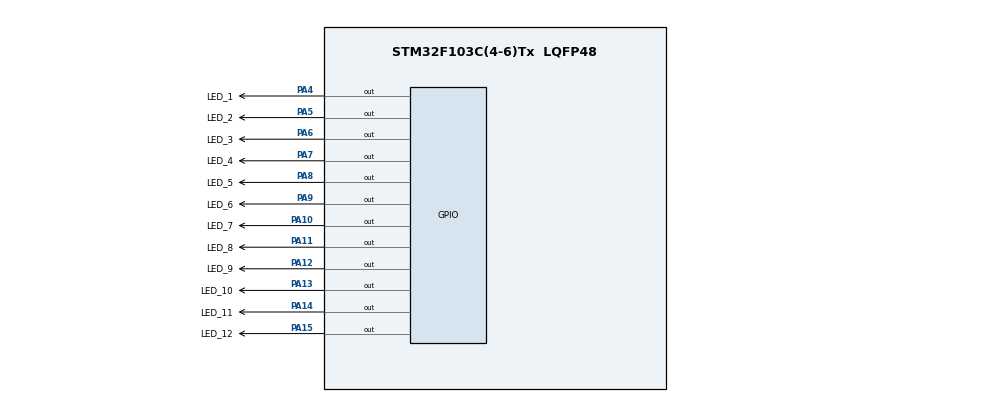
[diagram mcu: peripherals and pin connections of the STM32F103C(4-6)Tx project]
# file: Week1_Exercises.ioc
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Mcu.Family=STM32F1
Mcu.Name=STM32F103C(4-6)Tx
Mcu.Package=LQFP48
NVIC.PriorityGroup=NVIC_PRIORITYGROUP_4
PA10.GPIO_Label=LED_7
PA10.Signal=GPIO_Output
PA11.GPIO_Label=LED_8
PA11.Signal=GPIO_Output
PA12.GPIO_Label=LED_9
PA12.Signal=GPIO_Output
PA13.GPIO_Label=LED_10
PA13.Signal=GPIO_Output
PA14.GPIO_Label=LED_11
PA14.Signal=GPIO_Output
PA15.GPIO_Label=LED_12
PA15.Signal=GPIO_Output
PA4.GPIO_Label=LED_1
PA4.Signal=GPIO_Output
PA5.GPIO_Label=LED_2
PA5.Signal=GPIO_Output
PA6.GPIO_Label=LED_3
PA6.Signal=GPIO_Output
PA7.GPIO_Label=LED_4
PA7.Signal=GPIO_Output
PA8.GPIO_Label=LED_5
PA8.Signal=GPIO_Output
PA9.GPIO_Label=LED_6
PA9.Signal=GPIO_Output
ProjectManager.HeapSize=0x200
ProjectManager.StackSize=0x400
ProjectManager.TargetToolchain=STM32CubeIDE
RCC.APB1Freq_Value=8000000
RCC.APB2Freq_Value=8000000
VP_SYS_VS_ND.Mode=No_Debug
board=custom

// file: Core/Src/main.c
/* USER CODE BEGIN Header */
/**
  ******************************************************************************
  * @file           : main.c
  * @brief          : Main program body
  ******************************************************************************
  * @attention
  *
  * <h2><center>&copy; Copyright (c) 2021 STMicroelectronics.
  * All rights reserved.</center></h2>
  *
  * This software component is licensed by ST under BSD 3-Clause license,
  * the "License"; You may not use this file except in compliance with the
  * License. You may obtain a copy of the License at:
  *                        opensource.org/licenses/BSD-3-Clause
  *
  ******************************************************************************
  */
/* USER CODE END Header */
#include "main.h"
#include "led_display.h"

void SystemClock_Config(void);
static void MX_GPIO_Init(void);

int main(void)
{

  /* MCU Configuration--------------------------------------------------------*/

  /* Reset of all peripherals, Initializes the Flash interface and the Systick. */
  HAL_Init();

  /* Configure the system clock */
  SystemClock_Config();

  /* Initialize all configured peripherals */
  MX_GPIO_Init();

  /* Infinite loop */
  /* USER CODE BEGIN WHILE */
  int counter = 0;
  while (1)
  {
    /* USER CODE END WHILE */

    /* USER CODE BEGIN 3 */
	HAL_GPIO_WritePin (LED_1_RED_GPIO_Port, LED_1_RED_Pin, 0);
	HAL_GPIO_WritePin (LED_2_YELLOW_GPIO_Port, LED_2_YELLOW_Pin, 0);
	HAL_GPIO_WritePin (LED_3_GREEN_GPIO_Port, LED_3_GREEN_Pin, 0);
	HAL_GPIO_WritePin (LED_4_RED_GPIO_Port, LED_4_RED_Pin, 0);
	HAL_GPIO_WritePin (LED_5_YELLOW_GPIO_Port, LED_5_YELLOW_Pin, 0);
	HAL_GPIO_WritePin (LED_6_GREEN_GPIO_Port, LED_6_GREEN_Pin, 0);

	// Exercise 4: Count up
//	HAL_GPIO_WritePin (LED_1_RED_GPIO_Port, LED_1_RED_Pin, 1);
//
//	counter = 0;
//	while(counter >= 1){
//		HAL_GPIO_WritePin (LED_5_YELLOW_GPIO_Port, LED_5_YELLOW_Pin, 1);
//		update_seven_segment_led_buffer(counter--);
//		seven_segment_led_driver();
//		HAL_Delay(1000);
//	}
//	HAL_GPIO_WritePin (LED_5_YELLOW_GPIO_Port, LED_5_YELLOW_Pin, 0);
//	counter = 0;
//	while(counter >= 3){
//		HAL_GPIO_WritePin (LED_6_GREEN_GPIO_Port, LED_6_GREEN_Pin, 1);
//		update_seven_segment_led_buffer(counter--);
//		seven_segment_led_driver();
//		HAL_Delay(1000);
//	}
//	HAL_GPIO_WritePin (LED_6_GREEN_GPIO_Port, LED_6_GREEN_Pin, 0);
//
//	HAL_GPIO_WritePin (LED_4_RED_GPIO_Port, LED_4_RED_Pin, 1);
//
//	counter = 0;
//		while(counter >= 1){
//		HAL_GPIO_WritePin (LED_2_YELLOW_GPIO_Port, LED_2_YELLOW_Pin, 1);
//		update_seven_segment_led_buffer(counter--);
//		seven_segment_led_driver();
//		HAL_Delay(1000);
//		}
//	HAL_GPIO_WritePin (LED_2_YELLOW_GPIO_Port, LED_2_YELLOW_Pin, 0);
//	counter = 0;
//	while(counter >= 3){
//		HAL_GPIO_WritePin (LED_1_RED_GPIO_Port, LED_1_RED_Pin, 0);
//		HAL_GPIO_WritePin (LED_3_GREEN_GPIO_Port, LED_3_GREEN_Pin, 1);
//		update_seven_segment_led_buffer(counter--);
//		seven_segment_led_driver();
//		HAL_Delay(1000);
//	}
//	HAL_GPIO_WritePin (LED_3_GREEN_GPIO_Port, LED_3_GREEN_Pin, 0);

	// Exercise 5: Count down
	HAL_GPIO_WritePin (LED_1_RED_GPIO_Port, LED_1_RED_Pin, 1);

	counter = 1;
	while(counter >= 0){
		HAL_GPIO_WritePin (LED_5_YELLOW_GPIO_Port, LED_5_YELLOW_Pin, 1);
		update_seven_segment_led_buffer(counter--);
		seven_segment_led_driver();
		HAL_Delay(1000);
	}
	HAL_GPIO_WritePin (LED_5_YELLOW_GPIO_Port, LED_5_YELLOW_Pin, 0);
	counter = 3;
	while(counter >= 0){
		HAL_GPIO_WritePin (LED_6_GREEN_GPIO_Port, LED_6_GREEN_Pin, 1);
		update_seven_segment_led_buffer(counter--);
		seven_segment_led_driver();
		HAL_Delay(1000);
	}
	HAL_GPIO_WritePin (LED_6_GREEN_GPIO_Port, LED_6_GREEN_Pin, 0);

	HAL_GPIO_WritePin (LED_4_RED_GPIO_Port, LED_4_RED_Pin, 1);

	counter = 1;
		while(counter >= 0){
		HAL_GPIO_WritePin (LED_2_YELLOW_GPIO_Port, LED_2_YELLOW_Pin, 1);
		update_seven_segment_led_buffer(counter--);
		seven_segment_led_driver();
		HAL_Delay(1000);
		}
	HAL_GPIO_WritePin (LED_2_YELLOW_GPIO_Port, LED_2_YELLOW_Pin, 0);
	counter = 3;
	while(counter >= 0){
		HAL_GPIO_WritePin (LED_1_RED_GPIO_Port, LED_1_RED_Pin, 0);
		HAL_GPIO_WritePin (LED_3_GREEN_GPIO_Port, LED_3_GREEN_Pin, 1);
		update_seven_segment_led_buffer(counter--);
		seven_segment_led_driver();
		HAL_Delay(1000);
	}
	HAL_GPIO_WritePin (LED_3_GREEN_GPIO_Port, LED_3_GREEN_Pin, 0);
  }
  /* USER CODE END 3 */
}

void SystemClock_Config(void)
{
  RCC_OscInitTypeDef RCC_OscInitStruct = {0};
  RCC_ClkInitTypeDef RCC_ClkInitStruct = {0};

  /** Initializes the RCC Oscillators according to the specified parameters
  * in the RCC_OscInitTypeDef structure.
  */
  RCC_OscInitStruct.OscillatorType = RCC_OSCILLATORTYPE_HSI;
  RCC_OscInitStruct.HSIState = RCC_HSI_ON;
  RCC_OscInitStruct.HSICalibrationValue = RCC_HSICALIBRATION_DEFAULT;
  RCC_OscInitStruct.PLL.PLLState = RCC_PLL_NONE;
  if (HAL_RCC_OscConfig(&RCC_OscInitStruct) != HAL_OK)
  {
    Error_Handler();
  }
  /** Initializes the CPU, AHB and APB buses clocks
  */
  RCC_ClkInitStruct.ClockType = RCC_CLOCKTYPE_HCLK|RCC_CLOCKTYPE_SYSCLK
                              |RCC_CLOCKTYPE_PCLK1|RCC_CLOCKTYPE_PCLK2;
  RCC_ClkInitStruct.SYSCLKSource = RCC_SYSCLKSOURCE_HSI;
  RCC_ClkInitStruct.AHBCLKDivider = RCC_SYSCLK_DIV1;
  RCC_ClkInitStruct.APB1CLKDivider = RCC_HCLK_DIV1;
  RCC_ClkInitStruct.APB2CLKDivider = RCC_HCLK_DIV1;

  if (HAL_RCC_ClockConfig(&RCC_ClkInitStruct, FLASH_LATENCY_0) != HAL_OK)
  {
    Error_Handler();
  }
}

static void MX_GPIO_Init(void)
{
  GPIO_InitTypeDef GPIO_InitStruct = {0};

  /* GPIO Ports Clock Enable */
  __HAL_RCC_GPIOA_CLK_ENABLE();
  __HAL_RCC_GPIOB_CLK_ENABLE();

  /*Configure GPIO pin Output Level */
  HAL_GPIO_WritePin(GPIOA, LED_1_RED_Pin|LED_2_YELLOW_Pin|LED_3_GREEN_Pin|LED_4_RED_Pin
                          |LED_5_YELLOW_Pin|LED_6_GREEN_Pin, GPIO_PIN_RESET);

  /*Configure GPIO pin Output Level */
  HAL_GPIO_WritePin(GPIOB, SEV_SEG_0_Pin|SEV_SEG_1_Pin|SEV_SEG_2_Pin|SEV_SEG_3_Pin
                          |SEV_SEG_4_Pin|SEV_SEG_5_Pin|SEV_SEG_6_Pin, GPIO_PIN_RESET);

  /*Configure GPIO pins : LED_1_RED_Pin LED_2_YELLOW_Pin LED_3_GREEN_Pin LED_4_RED_Pin
                           LED_5_YELLOW_Pin LED_6_GREEN_Pin */
  GPIO_InitStruct.Pin = LED_1_RED_Pin|LED_2_YELLOW_Pin|LED_3_GREEN_Pin|LED_4_RED_Pin
                          |LED_5_YELLOW_Pin|LED_6_GREEN_Pin;
  GPIO_InitStruct.Mode = GPIO_MODE_OUTPUT_PP;
  GPIO_InitStruct.Pull = GPIO_NOPULL;
  GPIO_InitStruct.Speed = GPIO_SPEED_FREQ_LOW;
  HAL_GPIO_Init(GPIOA, &GPIO_InitStruct);

  /*Configure GPIO pins : SEV_SEG_0_Pin SEV_SEG_1_Pin SEV_SEG_2_Pin SEV_SEG_3_Pin
                           SEV_SEG_4_Pin SEV_SEG_5_Pin SEV_SEG_6_Pin */
  GPIO_InitStruct.Pin = SEV_SEG_0_Pin|SEV_SEG_1_Pin|SEV_SEG_2_Pin|SEV_SEG_3_Pin
                          |SEV_SEG_4_Pin|SEV_SEG_5_Pin|SEV_SEG_6_Pin;
  GPIO_InitStruct.Mode = GPIO_MODE_OUTPUT_PP;
  GPIO_InitStruct.Pull = GPIO_NOPULL;
  GPIO_InitStruct.Speed = GPIO_SPEED_FREQ_LOW;
  HAL_GPIO_Init(GPIOB, &GPIO_InitStruct);

}

void Error_Handler(void)
{
  __disable_irq();
  while (1)
  {
  }
}

/************************ (C) COPYRIGHT STMicroelectronics *****END OF FILE****/
